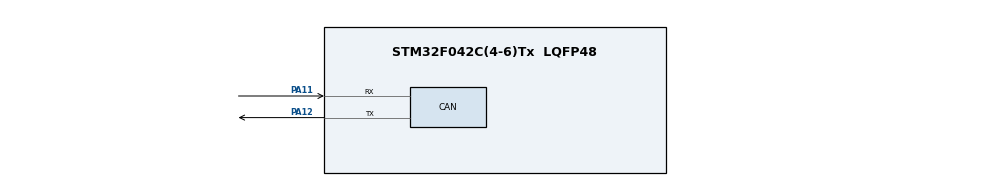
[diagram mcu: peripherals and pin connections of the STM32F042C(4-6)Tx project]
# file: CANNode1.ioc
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CAN.CalculateTimeQuantum=2000.0
Mcu.Family=STM32F0
Mcu.Name=STM32F042C(4-6)Tx
Mcu.Package=LQFP48
PA11.Mode=Master
PA11.Signal=CAN_RX
PA12.Mode=Master
PA12.Signal=CAN_TX
ProjectManager.HeapSize=0x200
ProjectManager.StackSize=0x400
ProjectManager.TargetToolchain=STM32CubeIDE
board=custom

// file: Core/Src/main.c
/* USER CODE BEGIN Header */
/**
  ******************************************************************************
  * @file           : main.c
  * @brief          : Main program body
  ******************************************************************************
  * @attention
  *
  * <h2><center>&copy; Copyright (c) 2021 STMicroelectronics.
  * All rights reserved.</center></h2>
  *
  * This software component is licensed by ST under BSD 3-Clause license,
  * the "License"; You may not use this file except in compliance with the
  * License. You may obtain a copy of the License at:
  *                        opensource.org/licenses/BSD-3-Clause
  *
  ******************************************************************************
  */
/* USER CODE END Header */
#include "main.h"

CAN_HandleTypeDef hcan;

void SystemClock_Config(void);
static void MX_GPIO_Init(void);
static void MX_CAN_Init(void);
void CAN_Transmit_Message(void);

/* USER CODE BEGIN 0 */
CAN_RxHeaderTypeDef rxHeader;
CAN_TxHeaderTypeDef txHeader;
uint8_t canRX[8] = {0,0,0,0,0,0,0,0};
CAN_FilterTypeDef canfil;
uint32_t canMailbox;
/* USER CODE END 0 */

int main(void)
{

  /* MCU Configuration--------------------------------------------------------*/

  /* Reset of all peripherals, Initializes the Flash interface and the Systick. */
  HAL_Init();

  /* Configure the system clock */
  SystemClock_Config();

  /* Initialize all configured peripherals */
  MX_GPIO_Init();
  MX_CAN_Init();
  /* USER CODE BEGIN 2 */

  canfil.FilterBank = 0;
  canfil.FilterMode = CAN_FILTERMODE_IDMASK;
  canfil.FilterFIFOAssignment = CAN_RX_FIFO0;
  canfil.FilterIdHigh = 0;
  canfil.FilterIdLow = 0;
  canfil.FilterMaskIdHigh = 0;
  canfil.FilterMaskIdLow = 0;
  canfil.FilterScale = CAN_FILTERSCALE_32BIT;
  canfil.FilterActivation = ENABLE;
  canfil.SlaveStartFilterBank = 0;

  txHeader.DLC = 8;
  txHeader.IDE = CAN_ID_STD;
  txHeader.RTR = CAN_RTR_DATA;
  txHeader.StdId = 0x018;
  txHeader.TransmitGlobalTime = DISABLE;

  HAL_CAN_ConfigFilter(&hcan,&canfil);
  HAL_CAN_Start(&hcan);
  HAL_CAN_ActivateNotification(&hcan,CAN_IT_RX_FIFO0_MSG_PENDING);

  /* USER CODE END 2 */

  /* Infinite loop */
  while (1)
  {

	 /*
	  uint8_t csend[] = {0x01,0x02,0x03,0x04,0x05,0x06,0x07,0x08};
	  HAL_CAN_AddTxMessage(&hcan,&txHeader,csend,&canMailbox);
	  HAL_GPIO_TogglePin (GPIOB, GPIO_PIN_12);
	  HAL_Delay(1000);
	  HAL_GPIO_TogglePin (GPIOB, GPIO_PIN_12);
	  HAL_Delay(1000);
	  */
  }
}

void CAN_Transmit_Message(void){
	CAN_TxHeaderTypeDef TxHeader;
	uint32_t TxMailbox;
	uint8_t msg = 'h';

	TxHeader.DLC = 1;
	TxHeader.StdId = 0x65D;
	TxHeader.IDE = CAN_ID_STD;
	TxHeader.RTR = CAN_RTR_DATA;
	if(HAL_CAN_GetTxMailboxesFreeLevel(&hcan)>0)
		if(HAL_CAN_AddTxMessage(&hcan, &TxHeader, &msg, &TxMailbox) == HAL_OK){
			HAL_GPIO_TogglePin (GPIOB, GPIO_PIN_12);
			HAL_GPIO_TogglePin (GPIOB, GPIO_PIN_13);
			HAL_GPIO_TogglePin (GPIOB, GPIO_PIN_14);
		}
			//Error_Handler();

	//while(HAL_CAN_IsTxMessagePending(&hcan, TxMailbox));

}

void SystemClock_Config(void)
{
  RCC_OscInitTypeDef RCC_OscInitStruct = {0};
  RCC_ClkInitTypeDef RCC_ClkInitStruct = {0};

  /** Initializes the RCC Oscillators according to the specified parameters
  * in the RCC_OscInitTypeDef structure.
  */
  RCC_OscInitStruct.OscillatorType = RCC_OSCILLATORTYPE_HSI;
  RCC_OscInitStruct.HSIState = RCC_HSI_ON;
  RCC_OscInitStruct.HSICalibrationValue = RCC_HSICALIBRATION_DEFAULT;
  RCC_OscInitStruct.PLL.PLLState = RCC_PLL_NONE;
  if (HAL_RCC_OscConfig(&RCC_OscInitStruct) != HAL_OK)
  {
    Error_Handler();
  }
  /** Initializes the CPU, AHB and APB buses clocks
  */
  RCC_ClkInitStruct.ClockType = RCC_CLOCKTYPE_HCLK|RCC_CLOCKTYPE_SYSCLK
                              |RCC_CLOCKTYPE_PCLK1;
  RCC_ClkInitStruct.SYSCLKSource = RCC_SYSCLKSOURCE_HSI;
  RCC_ClkInitStruct.AHBCLKDivider = RCC_SYSCLK_DIV1;
  RCC_ClkInitStruct.APB1CLKDivider = RCC_HCLK_DIV1;

  if (HAL_RCC_ClockConfig(&RCC_ClkInitStruct, FLASH_LATENCY_0) != HAL_OK)
  {
    Error_Handler();
  }
}

static void MX_CAN_Init(void)
{

  hcan.Instance = CAN;
  hcan.Init.Prescaler = 16;
  hcan.Init.Mode = CAN_MODE_NORMAL;
  hcan.Init.SyncJumpWidth = CAN_SJW_1TQ;
  hcan.Init.TimeSeg1 = CAN_BS1_2TQ;
  hcan.Init.TimeSeg2 = CAN_BS2_1TQ;
  hcan.Init.TimeTriggeredMode = DISABLE;
  hcan.Init.AutoBusOff = DISABLE;
  hcan.Init.AutoWakeUp = DISABLE;
  hcan.Init.AutoRetransmission = ENABLE;
  hcan.Init.ReceiveFifoLocked = DISABLE;
  hcan.Init.TransmitFifoPriority = DISABLE;
  if (HAL_CAN_Init(&hcan) != HAL_OK)
  {
    Error_Handler();
  }

}

static void MX_GPIO_Init(void)
{

	GPIO_InitTypeDef GPIO_InitStruct = {0};

	  /* GPIO Ports Clock Enable */
	  __HAL_RCC_GPIOB_CLK_ENABLE();
	  __HAL_RCC_GPIOA_CLK_ENABLE();

	  /*Configure GPIO pin Output Level */
	  HAL_GPIO_WritePin(GPIOB, GPIO_PIN_12|GPIO_PIN_13|GPIO_PIN_14, GPIO_PIN_RESET);

	  /*Configure GPIO pins : PB12 PB13 PB14 */
	  GPIO_InitStruct.Pin = GPIO_PIN_12|GPIO_PIN_13|GPIO_PIN_14;
	  GPIO_InitStruct.Mode = GPIO_MODE_OUTPUT_PP;
	  GPIO_InitStruct.Pull = GPIO_NOPULL;
	  GPIO_InitStruct.Speed = GPIO_SPEED_FREQ_LOW;
	  HAL_GPIO_Init(GPIOB, &GPIO_InitStruct);

}

void Error_Handler(void)
{
}

/************************ (C) COPYRIGHT STMicroelectronics *****END OF FILE****/
